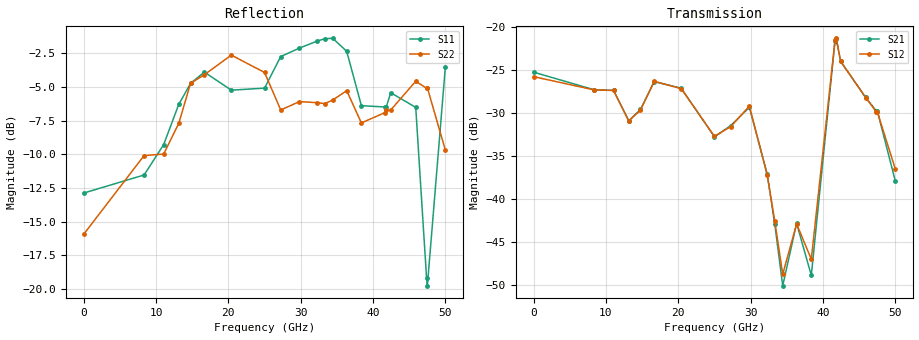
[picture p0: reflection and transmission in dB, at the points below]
!Keysight Technologies,N5245B,MY58422270,A.16.20.02
!Date: Thursday, March 05, 2026 01:32:42
!Correction: S11(C  2-Port  )
!S21(C  2-Port  )
!S12(C  2-Port  )
!S22(C  2-Port  )
!S2P File: Measurements: S11, S21, S12, S22:
# Hz S  dB  R 50
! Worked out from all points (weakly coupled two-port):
!   3201 points, 10 MHz to 50 GHz, reference 50 ohm
!   highest |S21| = -21.41 dB at 41.85 GHz (marker M1); lowest = -50.1 dB at 34.44 GHz (marker M2)
!   lowest |S11| = -19.7 dB at 47.52 GHz (marker M3), VSWR 1.23, Z = 45.4 + j8.73 ohm
!   |S11| at or under -10 dB: start of sweep to 10.09 GHz; 11.36 GHz to 11.92 GHz (560.1 MHz wide, 4.81 % of centre); 46.67 GHz to 48.28 GHz (1.614 GHz wide, 3.4 % of centre)
!   |S22| runs from -20.9 to -2.6 dB; largest |S21 - S12| = 0.0079
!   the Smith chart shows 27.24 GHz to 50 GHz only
!   S11 on the Smith chart (normalised r, x): 27.24 GHz: 0.18, +0.37; 32.3 GHz: 0.42, +1.86; 36.36 GHz: 2.39, -3.37; 42.45 GHz: 1.00, -1.26; 47.41 GHz: 0.84, +0.13; 50 GHz: 0.62, -1.35
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1e7  -12.87 -3.9  -25.26 4.4  -25.78 1.8  -15.92 41.4
8.352081e9  -11.53 175.2  -27.30 28.9  -27.32 29.1  -10.09 -179.0
1.105467e10  -9.28 110.3  -27.37 -70.6  -27.39 -70.3  -9.98 83.2
1.3148e10  -6.29 64.7  -30.93 -126.9  -30.93 -127.1  -7.70 -24.1
1.477267e10  -4.74 12.8  -29.60 -149.4  -29.69 -149.5  -4.73 -91.4
1.667854e10  -3.90 -43.8  -26.35 158.5  -26.32 158.8  -4.10 -141.3
2.041217e10  -5.24 -121.7  -27.13 39.4  -27.18 39.2  -2.64 154.9
2.5005e10  -5.09 -179.9  -32.79 -65.9  -32.73 -66.3  -3.93 71.6
2.723893e10  -2.75 138.8  -31.48 -114.8  -31.61 -114.9  -6.71 31.5
2.983216e10  -2.12 93.7  -29.35 159.0  -29.21 159.2  -6.09 -28.7
3.230042e10  -1.60 54.7  -37.17 47.3  -37.20 47.1  -6.17 -103.7
3.334708e10  -1.42 36.1  -42.98 1.1  -42.63 1.3  -6.24 -126.8
3.444061e10  -1.40 16.5  -50.12 -107.8  -48.79 -97.4  -5.97 -149.9
3.63621e10  -2.36 -22.7  -42.86 114.9  -42.92 115.2  -5.28 173.8
3.839295e10  -6.39 -22.5  -48.92 -101.3  -47.04 57.0  -7.67 141.2
4.167354e10  -6.49 -52.6  -21.60 -53.5  -21.52 -54.0  -6.90 115.2
4.184538e10  -6.46 -52.5  -21.41 -69.8  -21.32 -69.9  -6.73 113.6
4.245463e10  -5.43 -57.8  -24.01 -114.9  -24.01 -114.5  -6.71 109.8
4.590707e10  -6.52 -117.5  -28.20 50.1  -28.21 49.8  -4.58 62.6
4.740677e10  -19.19 137.7  -29.80 -3.2  -29.91 -1.3  -5.10 43.4
4.751612e10  -19.74 112.6  -29.74 -5.0  -29.87 -3.3  -5.07 42.2
5e10  -3.53 -66.1  -37.91 -141.8  -36.51 -121.2  -9.68 4.6
